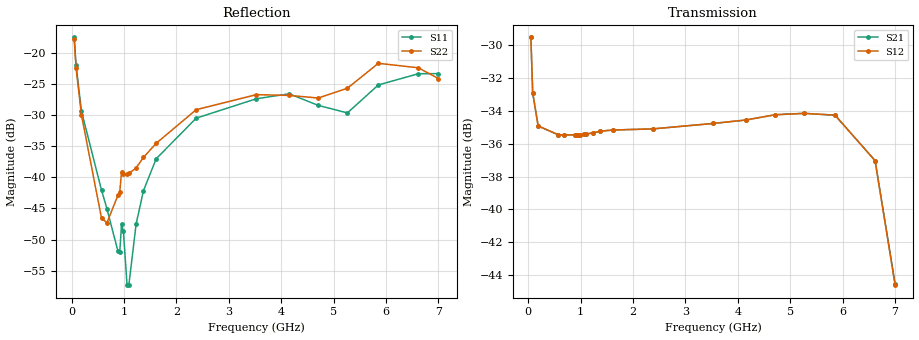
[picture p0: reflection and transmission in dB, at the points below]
! Integrated Device Technology
! Corporate Headquarters
! 6024 Silver Creek Valley Road
! San Jose, CA 95138  USA
! Phone:  1-408-284-8200
! Toll Free:  1-800-223-1366
! Webpage:  http://www.idt.com/
! Timing and RF Division
! 515 Groton Road, Suite 102
! Westford, MA 01886-6024
! Device:  F2258
! Description: Voltage Variable RF Attenuator
! Frequency:  50.0 -  6000.00 MHz
! Package:  3x3 mm Thin QFN Plastic Package: 16 pin
! Ports:  2 RF, 2 DC
!  Pin  1  = NC
!  Pin  2  = NC
!  Pin  3  = RF2  = Port 2
!  Pin  4  = GND
!  Pin  5  = Vdd
!  Pin  6  = NC
!  Pin  7  = VCTRL
!  Pin  8  = NC
!  Pin  9  = GND
!  Pin 10  = RF1  = Port 1
!  Pin 11  = NC
!  Pin 12  = NC
!  Pin 13  = NC
!  Pin 14  = NC
!  Pin 15  = NC
!  Pin 16  = NC
! Vcntrl:  2.350 Volts
! Vdd:  +3.300 Volts
! Current:  1.148 mA
! Data:  The device was measured on a the F2258 evaluation board which has
!  individual transmission lines to the RF pins.  Data was collected
!  using a calibrated network analyzer.  The evaluation board was
!  de-embedded using a TRL calibration technique.
!  The reference plane is the edge of the package pin.
! Misc:  SN 10
!  Action Tracker AT0285
! Date Measured:  2014-12-10
! Date:  2016-01-13  MJV
! Note:
!  Integrated Device Technology supplies this data as a sample of measured
!  data at the package pin for this product.  Your particular data for this
!  product may vary.
!  Data was taken at 25 degrees C.
!  Integrated Device Technology reserves the right to change this data at anytime.
!Freq_(GHz)  S11M_(dB)  S11P_(deg)  S21M_(dB)  S21P_(deg)  S12M_(dB)  S12P_(deg)  S22M_(dB)  S22P_(deg)
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# GHz S dB R 50
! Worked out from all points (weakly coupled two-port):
!   201 points, 50 MHz to 7 GHz, reference 50 ohm
!   highest |S21| = -29.53 dB at 50 MHz (marker M1); lowest = -44.5 dB at 7 GHz (marker M2)
!   lowest |S11| = -57.3 dB at 1.093 GHz (marker M3), VSWR 1.00, Z = 49.9 + j0.114 ohm
!   |S11| at or under -10 dB: start of sweep to end of sweep
!   |S22| runs from -47.3 to -17.8 dB; largest |S21 - S12| = 6.8e-05
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0.05  -17.56 -111.0  -29.53 -68.6  -29.53 -68.6  -17.79 -111.6
0.08475  -21.98 -107.5  -32.90 -48.9  -32.90 -48.8  -22.44 -108.2
0.189  -29.42 -109.5  -34.92 -24.8  -34.92 -24.8  -30.03 -111.5
0.57125  -42.07 -124.8  -35.46 -10.4  -35.45 -10.4  -46.58 -168.9
0.6755  -45.07 -132.3  -35.47 -9.4  -35.47 -9.4  -47.29 151.6
0.884  -51.87 166.5  -35.47 -8.4  -35.47 -8.4  -42.90 123.7
0.91875  -52.02 150.5  -35.46 -8.3  -35.46 -8.3  -42.39 122.0
0.9535  -47.56 -163.3  -35.47 -8.2  -35.47 -8.2  -39.20 125.9
0.98825  -48.61 -174.6  -35.46 -8.1  -35.46 -8.1  -39.50 123.7
1.05775  -57.26 154.7  -35.43 -7.9  -35.44 -7.9  -39.56 110.1
1.0925  -57.31 123.2  -35.42 -7.9  -35.42 -7.9  -39.39 106.0
1.2315  -47.49 47.1  -35.35 -7.9  -35.34 -7.9  -38.50 84.5
1.3705  -42.19 37.2  -35.24 -8.3  -35.24 -8.3  -36.83 70.9
1.61375  -37.04 33.0  -35.17 -9.6  -35.17 -9.6  -34.56 56.4
2.37825  -30.52 48.2  -35.10 -13.1  -35.10 -13.1  -29.16 45.1
3.525  -27.41 91.6  -34.77 -19.5  -34.77 -19.5  -26.75 68.6
4.1505  -26.61 105.0  -34.56 -23.9  -34.56 -23.9  -26.87 76.0
4.7065  -28.47 95.7  -34.24 -28.6  -34.24 -28.6  -27.29 59.7
5.2625  -29.68 54.3  -34.15 -34.8  -34.16 -34.7  -25.72 22.5
5.85325  -25.19 29.9  -34.27 -45.4  -34.26 -45.3  -21.72 -1.8
6.61775  -23.39 49.7  -37.03 -68.6  -37.04 -68.6  -22.44 -43.7
7  -23.37 84.5  -44.54 -61.4  -44.61 -61.0  -24.17 -130.1
